VERSION 5.8 ;
BUSBITCHARS "[]" ;
DIVIDERCHAR "/" ;
UNITS
    DATABASE MICRONS 1000 ;
END UNITS

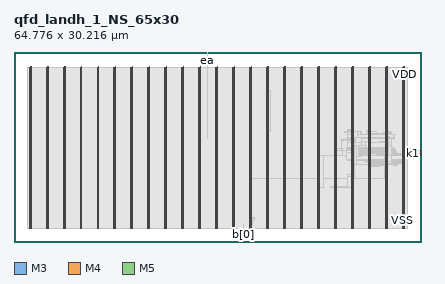
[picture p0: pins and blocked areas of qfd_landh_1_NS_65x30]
MACRO qfd_landh_1_NS_65x30
  FOREIGN qfd_landh_1_NS_65x30 0 0 ;
  CLASS BLOCK ;
  SIZE 64.776 BY 30.216 ;
  PIN a[0]
    DIRECTION INPUT ;
    USE SIGNAL ;
    PORT
      LAYER M3 ;
        RECT  30.708 30.179 30.726 30.216 ;
    END
  END a[0]
  PIN b[0]
    DIRECTION OUTPUT ;
    USE SIGNAL ;
    PORT
      LAYER M3 ;
        RECT  36.468 0 36.486 0.037 ;
    END
  END b[0]
  PIN ck
    DIRECTION INPUT ;
    USE SIGNAL ;
    PORT
      LAYER M4 ;
        RECT  64.692 13.68 64.776 13.704 ;
    END
  END ck
  PIN ckf
    DIRECTION INPUT ;
    USE SIGNAL ;
    PORT
      LAYER M4 ;
        RECT  64.692 13.776 64.776 13.8 ;
    END
  END ckf
  PIN ea
    DIRECTION INPUT ;
    USE SIGNAL ;
    PORT
      LAYER M3 ;
        RECT  30.78 30.179 30.798 30.216 ;
    END
  END ea
  PIN fault
    DIRECTION OUTPUT ;
    USE SIGNAL ;
    PORT
      LAYER M4 ;
        RECT  64.692 13.872 64.776 13.896 ;
    END
  END fault
  PIN k0
    DIRECTION INPUT ;
    USE SIGNAL ;
    PORT
      LAYER M4 ;
        RECT  64.692 13.968 64.776 13.992 ;
    END
  END k0
  PIN k1
    DIRECTION INPUT ;
    USE SIGNAL ;
    PORT
      LAYER M4 ;
        RECT  64.692 14.064 64.776 14.088 ;
    END
  END k1
  PIN k2
    DIRECTION INPUT ;
    USE SIGNAL ;
    PORT
      LAYER M4 ;
        RECT  64.692 14.16 64.776 14.184 ;
    END
  END k2
  PIN rs
    DIRECTION INPUT ;
    USE SIGNAL ;
    PORT
      LAYER M4 ;
        RECT  64.692 14.256 64.776 14.28 ;
    END
  END rs
  PIN tie_hi
    DIRECTION OUTPUT ;
    USE SIGNAL ;
    PORT
      LAYER M4 ;
        RECT  64.692 14.352 64.776 14.376 ;
    END
  END tie_hi
  PIN tie_lo
    DIRECTION OUTPUT ;
    USE SIGNAL ;
    PORT
      LAYER M4 ;
        RECT  64.692 14.448 64.776 14.472 ;
    END
  END tie_lo
  PIN VDD
    DIRECTION INOUT ;
    USE POWER ;
    PORT
      LAYER M5 ;
        RECT  61.992 2.151 62.112 27.833 ;
        RECT  59.292 2.151 59.412 27.833 ;
        RECT  56.592 2.151 56.712 27.833 ;
        RECT  53.892 2.151 54.012 27.833 ;
        RECT  51.192 2.151 51.312 27.833 ;
        RECT  48.492 2.151 48.612 27.833 ;
        RECT  45.792 2.151 45.912 27.833 ;
        RECT  43.092 2.151 43.212 27.833 ;
        RECT  40.392 2.151 40.512 27.833 ;
        RECT  37.692 2.151 37.812 27.833 ;
        RECT  34.992 2.151 35.112 27.833 ;
        RECT  32.292 2.151 32.412 27.833 ;
        RECT  29.592 2.151 29.712 27.833 ;
        RECT  26.892 2.151 27.012 27.833 ;
        RECT  24.192 2.151 24.312 27.833 ;
        RECT  21.492 2.151 21.612 27.833 ;
        RECT  18.792 2.151 18.912 27.833 ;
        RECT  16.092 2.151 16.212 27.833 ;
        RECT  13.392 2.151 13.512 27.833 ;
        RECT  10.692 2.151 10.812 27.833 ;
        RECT  7.992 2.151 8.112 27.833 ;
        RECT  5.292 2.151 5.412 27.833 ;
        RECT  2.592 2.151 2.712 27.833 ;
    END
  END VDD
  PIN VSS
    DIRECTION INOUT ;
    USE GROUND ;
    PORT
      LAYER M5 ;
        RECT  61.8 2.137 61.92 27.819 ;
        RECT  59.1 2.137 59.22 27.819 ;
        RECT  56.4 2.137 56.52 27.819 ;
        RECT  53.7 2.137 53.82 27.819 ;
        RECT  51 2.137 51.12 27.819 ;
        RECT  48.3 2.137 48.42 27.819 ;
        RECT  45.6 2.137 45.72 27.819 ;
        RECT  42.9 2.137 43.02 27.819 ;
        RECT  40.2 2.137 40.32 27.819 ;
        RECT  37.5 2.137 37.62 27.819 ;
        RECT  34.8 2.137 34.92 27.819 ;
        RECT  32.1 2.137 32.22 27.819 ;
        RECT  29.4 2.137 29.52 27.819 ;
        RECT  26.7 2.137 26.82 27.819 ;
        RECT  24 2.137 24.12 27.819 ;
        RECT  21.3 2.137 21.42 27.819 ;
        RECT  18.6 2.137 18.72 27.819 ;
        RECT  15.9 2.137 16.02 27.819 ;
        RECT  13.2 2.137 13.32 27.819 ;
        RECT  10.5 2.137 10.62 27.819 ;
        RECT  7.8 2.137 7.92 27.819 ;
        RECT  5.1 2.137 5.22 27.819 ;
        RECT  2.4 2.137 2.52 27.819 ;
    END
  END VSS
  OBS
    LAYER RVTN ;
     RECT  2.16 2.16 62.586 2.295 ;
     RECT  2.16 2.565 62.586 2.835 ;
     RECT  2.16 3.105 62.586 3.375 ;
     RECT  2.16 3.645 62.586 3.915 ;
     RECT  2.16 4.185 62.586 4.455 ;
     RECT  2.16 4.725 62.586 4.995 ;
     RECT  2.16 5.265 62.586 5.535 ;
     RECT  2.16 5.805 62.586 6.075 ;
     RECT  2.16 6.345 62.586 6.615 ;
     RECT  2.16 6.885 62.586 7.155 ;
     RECT  2.16 7.425 62.586 7.695 ;
     RECT  2.16 7.965 62.586 8.235 ;
     RECT  2.16 8.505 62.586 8.775 ;
     RECT  2.16 9.045 62.586 9.315 ;
     RECT  2.16 9.585 62.586 9.855 ;
     RECT  2.16 10.125 62.586 10.395 ;
     RECT  2.16 10.665 62.586 10.935 ;
     RECT  2.16 11.205 62.586 11.475 ;
     RECT  2.16 11.745 62.586 12.015 ;
     RECT  2.16 12.285 62.586 12.555 ;
     RECT  2.16 12.825 62.586 13.095 ;
     RECT  2.16 13.365 62.586 13.635 ;
     RECT  2.16 13.905 62.586 14.175 ;
     RECT  2.16 14.445 62.586 14.715 ;
     RECT  2.16 14.985 62.586 15.255 ;
     RECT  2.16 15.525 62.586 15.795 ;
     RECT  2.16 16.065 62.586 16.335 ;
     RECT  2.16 16.605 62.586 16.875 ;
     RECT  2.16 17.145 62.586 17.415 ;
     RECT  2.16 17.685 62.586 17.955 ;
     RECT  2.16 18.225 62.586 18.495 ;
     RECT  2.16 18.765 62.586 19.035 ;
     RECT  2.16 19.305 62.586 19.575 ;
     RECT  2.16 19.845 62.586 20.115 ;
     RECT  2.16 20.385 62.586 20.655 ;
     RECT  2.16 20.925 62.586 21.195 ;
     RECT  2.16 21.465 62.586 21.735 ;
     RECT  2.16 22.005 62.586 22.275 ;
     RECT  2.16 22.545 62.586 22.815 ;
     RECT  2.16 23.085 62.586 23.355 ;
     RECT  2.16 23.625 62.586 23.895 ;
     RECT  2.16 24.165 62.586 24.435 ;
     RECT  2.16 24.705 62.586 24.975 ;
     RECT  2.16 25.245 62.586 25.515 ;
     RECT  2.16 25.785 62.586 26.055 ;
     RECT  2.16 26.325 62.586 26.595 ;
     RECT  2.16 26.865 62.586 27.135 ;
     RECT  2.16 27.405 62.586 27.675 ;
    LAYER RVTP ;
     RECT  2.16 2.295 62.586 2.565 ;
     RECT  2.16 2.835 62.586 3.105 ;
     RECT  2.16 3.375 62.586 3.645 ;
     RECT  2.16 3.915 62.586 4.185 ;
     RECT  2.16 4.455 62.586 4.725 ;
     RECT  2.16 4.995 62.586 5.265 ;
     RECT  2.16 5.535 62.586 5.805 ;
     RECT  2.16 6.075 62.586 6.345 ;
     RECT  2.16 6.615 62.586 6.885 ;
     RECT  2.16 7.155 62.586 7.425 ;
     RECT  2.16 7.695 62.586 7.965 ;
     RECT  2.16 8.235 62.586 8.505 ;
     RECT  2.16 8.775 62.586 9.045 ;
     RECT  2.16 9.315 62.586 9.585 ;
     RECT  2.16 9.855 62.586 10.125 ;
     RECT  2.16 10.395 62.586 10.665 ;
     RECT  2.16 10.935 62.586 11.205 ;
     RECT  2.16 11.475 62.586 11.745 ;
     RECT  2.16 12.015 62.586 12.285 ;
     RECT  2.16 12.555 62.586 12.825 ;
     RECT  2.16 13.095 62.586 13.365 ;
     RECT  2.16 13.635 62.586 13.905 ;
     RECT  2.16 14.175 62.586 14.445 ;
     RECT  2.16 14.715 62.586 14.985 ;
     RECT  2.16 15.255 62.586 15.525 ;
     RECT  2.16 15.795 62.586 16.065 ;
     RECT  2.16 16.335 62.586 16.605 ;
     RECT  2.16 16.875 62.586 17.145 ;
     RECT  2.16 17.415 62.586 17.685 ;
     RECT  2.16 17.955 62.586 18.225 ;
     RECT  2.16 18.495 62.586 18.765 ;
     RECT  2.16 19.035 62.586 19.305 ;
     RECT  2.16 19.575 62.586 19.845 ;
     RECT  2.16 20.115 62.586 20.385 ;
     RECT  2.16 20.655 62.586 20.925 ;
     RECT  2.16 21.195 62.586 21.465 ;
     RECT  2.16 21.735 62.586 22.005 ;
     RECT  2.16 22.275 62.586 22.545 ;
     RECT  2.16 22.815 62.586 23.085 ;
     RECT  2.16 23.355 62.586 23.625 ;
     RECT  2.16 23.895 62.586 24.165 ;
     RECT  2.16 24.435 62.586 24.705 ;
     RECT  2.16 24.975 62.586 25.245 ;
     RECT  2.16 25.515 62.586 25.785 ;
     RECT  2.16 26.055 62.586 26.325 ;
     RECT  2.16 26.595 62.586 26.865 ;
     RECT  2.16 27.135 62.586 27.405 ;
     RECT  2.16 27.675 62.586 27.81 ;
    LAYER M1 ;
     RECT  2.16 2.151 62.586 27.819 ;
    LAYER M2 ;
     RECT  2.16 2.151 62.586 27.819 ;
     RECT  62.586 13.536 62.699 15.012 ;
     RECT  62.699 13.536 63.887 14.94 ;
     RECT  63.887 14.922 63.923 14.94 ;
     RECT  63.887 13.842 63.959 14.13 ;
     RECT  63.959 14.112 63.995 14.13 ;
    LAYER M3 ;
     RECT  2.415 2.143 2.505 2.413 ;
     RECT  5.115 2.143 5.205 2.413 ;
     RECT  7.815 2.143 7.905 2.413 ;
     RECT  10.515 2.143 10.605 2.413 ;
     RECT  13.215 2.143 13.305 2.413 ;
     RECT  15.915 2.143 16.005 2.413 ;
     RECT  18.615 2.143 18.705 2.413 ;
     RECT  21.315 2.143 21.405 2.413 ;
     RECT  24.015 2.143 24.105 2.413 ;
     RECT  26.715 2.143 26.805 2.413 ;
     RECT  29.415 2.143 29.505 2.413 ;
     RECT  32.115 2.143 32.205 2.413 ;
     RECT  34.815 2.143 34.905 2.413 ;
     RECT  37.515 2.143 37.605 2.413 ;
     RECT  40.215 2.143 40.305 2.413 ;
     RECT  42.915 2.143 43.005 2.413 ;
     RECT  45.615 2.143 45.705 2.413 ;
     RECT  48.315 2.143 48.405 2.413 ;
     RECT  51.015 2.143 51.105 2.413 ;
     RECT  53.715 2.143 53.805 2.413 ;
     RECT  56.415 2.143 56.505 2.413 ;
     RECT  59.115 2.143 59.205 2.413 ;
     RECT  61.815 2.143 61.905 2.413 ;
     RECT  36.468 0.012 36.486 2.759 ;
     RECT  37.515 2.413 37.797 2.803 ;
     RECT  37.515 2.803 37.854 3.379 ;
     RECT  37.515 3.379 38.214 3.685 ;
     RECT  37.44 3.685 38.214 3.725 ;
     RECT  37.515 3.725 38.214 3.839 ;
     RECT  37.515 3.839 37.998 3.875 ;
     RECT  51.015 2.413 51.297 8.671 ;
     RECT  48.315 2.413 48.597 8.731 ;
     RECT  50.328 8.671 51.297 8.765 ;
     RECT  48.315 8.731 49.014 8.771 ;
     RECT  37.515 3.875 37.797 9.883 ;
     RECT  45.615 2.413 45.897 10.027 ;
     RECT  37.515 9.883 37.89 10.061 ;
     RECT  53.715 2.413 53.997 10.123 ;
     RECT  38.772 10.027 38.79 10.157 ;
     RECT  45.615 10.027 45.99 10.157 ;
     RECT  46.764 10.027 46.782 10.157 ;
     RECT  53.715 10.123 54.126 10.165 ;
     RECT  53.028 10.165 54.126 10.355 ;
     RECT  53.064 10.355 54.126 10.471 ;
     RECT  53.064 10.471 54.198 10.541 ;
     RECT  53.064 10.541 53.997 10.739 ;
     RECT  56.415 2.413 56.697 11.947 ;
     RECT  56.415 11.947 57.402 12.019 ;
     RECT  56.415 12.019 57.474 12.055 ;
     RECT  56.415 12.055 58.122 12.091 ;
     RECT  59.115 2.413 59.397 12.091 ;
     RECT  60.444 12.091 60.966 12.217 ;
     RECT  56.415 12.091 59.454 12.283 ;
     RECT  56.415 12.283 59.598 12.361 ;
     RECT  60.336 12.217 60.966 12.361 ;
     RECT  56.415 12.361 60.966 12.523 ;
     RECT  56.415 12.523 61.002 12.595 ;
     RECT  61.815 2.413 62.097 12.595 ;
     RECT  56.415 12.595 62.097 12.721 ;
     RECT  56.268 12.721 62.097 12.757 ;
     RECT  56.088 12.757 62.097 12.829 ;
     RECT  53.715 10.739 53.997 12.865 ;
     RECT  53.64 12.865 54.414 12.901 ;
     RECT  55.692 12.829 62.097 12.901 ;
     RECT  53.064 12.901 54.594 13.027 ;
     RECT  55.368 12.901 62.097 13.027 ;
     RECT  53.064 13.027 62.097 13.051 ;
     RECT  52.884 13.051 62.097 13.091 ;
     RECT  53.496 13.091 62.097 13.771 ;
     RECT  63.864 13.531 63.882 13.837 ;
     RECT  53.496 13.771 62.73 13.909 ;
     RECT  63.864 13.837 63.954 14.107 ;
     RECT  53.244 13.909 62.73 14.135 ;
     RECT  53.244 14.135 60.822 14.203 ;
     RECT  63.864 14.107 63.99 14.285 ;
     RECT  52.776 14.203 60.822 14.369 ;
     RECT  61.815 14.135 62.73 14.443 ;
     RECT  63.864 14.285 63.918 14.443 ;
     RECT  52.776 14.369 60.714 14.525 ;
     RECT  52.92 14.525 60.714 14.549 ;
     RECT  52.92 14.549 60.642 14.639 ;
     RECT  61.815 14.443 63.918 14.639 ;
     RECT  52.92 14.639 60.57 14.909 ;
     RECT  63.9 14.639 63.918 14.945 ;
     RECT  52.92 14.909 60.426 15.017 ;
     RECT  61.815 14.639 62.694 15.017 ;
     RECT  53.028 15.017 60.426 15.053 ;
     RECT  53.028 15.053 60.03 15.755 ;
     RECT  52.092 14.827 52.11 16.033 ;
     RECT  52.092 16.033 52.254 16.105 ;
     RECT  53.028 15.755 54.27 16.105 ;
     RECT  52.092 16.105 54.27 16.259 ;
     RECT  52.092 16.259 52.11 16.403 ;
     RECT  52.884 16.259 54.27 16.403 ;
     RECT  55.188 15.755 60.03 16.501 ;
     RECT  52.992 16.403 54.27 16.555 ;
     RECT  55.188 16.501 60.462 16.555 ;
     RECT  52.992 16.555 60.462 17.069 ;
     RECT  52.992 17.069 60.246 17.105 ;
     RECT  56.124 17.105 59.958 17.249 ;
     RECT  58.68 17.249 59.958 17.339 ;
     RECT  58.68 17.339 59.814 17.411 ;
     RECT  52.992 17.105 55.314 17.491 ;
     RECT  52.596 17.491 55.314 17.609 ;
     RECT  56.124 17.249 57.69 17.609 ;
     RECT  59.115 17.411 59.814 17.609 ;
     RECT  40.215 2.413 40.497 17.617 ;
     RECT  52.992 17.609 54.054 17.645 ;
     RECT  55.044 17.609 55.062 17.645 ;
     RECT  57.672 17.609 57.69 17.645 ;
     RECT  52.992 17.645 53.997 17.681 ;
     RECT  56.124 17.609 56.697 17.681 ;
     RECT  53.064 17.681 53.997 17.879 ;
     RECT  40.215 17.617 40.77 24.089 ;
     RECT  30.708 16.537 30.726 24.097 ;
     RECT  2.415 2.413 2.697 27.557 ;
     RECT  5.115 2.413 5.397 27.557 ;
     RECT  7.815 2.413 8.097 27.557 ;
     RECT  10.515 2.413 10.797 27.557 ;
     RECT  13.215 2.413 13.497 27.557 ;
     RECT  15.915 2.413 16.197 27.557 ;
     RECT  18.615 2.413 18.897 27.557 ;
     RECT  21.315 2.413 21.597 27.557 ;
     RECT  24.015 2.413 24.297 27.557 ;
     RECT  26.715 2.413 26.997 27.557 ;
     RECT  29.415 2.413 29.697 27.557 ;
     RECT  32.115 2.413 32.397 27.557 ;
     RECT  34.815 2.413 35.097 27.557 ;
     RECT  37.515 10.061 37.797 27.557 ;
     RECT  40.215 24.089 40.497 27.557 ;
     RECT  42.915 2.413 43.197 27.557 ;
     RECT  45.615 10.157 45.897 27.557 ;
     RECT  48.315 8.771 48.597 27.557 ;
     RECT  51.015 8.765 51.297 27.557 ;
     RECT  53.715 17.879 53.997 27.557 ;
     RECT  56.415 17.681 56.697 27.557 ;
     RECT  59.115 17.609 59.397 27.557 ;
     RECT  61.815 15.017 62.097 27.557 ;
     RECT  2.607 27.557 2.697 27.827 ;
     RECT  5.307 27.557 5.397 27.827 ;
     RECT  8.007 27.557 8.097 27.827 ;
     RECT  10.707 27.557 10.797 27.827 ;
     RECT  13.407 27.557 13.497 27.827 ;
     RECT  16.107 27.557 16.197 27.827 ;
     RECT  18.807 27.557 18.897 27.827 ;
     RECT  21.507 27.557 21.597 27.827 ;
     RECT  24.207 27.557 24.297 27.827 ;
     RECT  26.907 27.557 26.997 27.827 ;
     RECT  29.607 27.557 29.697 27.827 ;
     RECT  32.307 27.557 32.397 27.827 ;
     RECT  35.007 27.557 35.097 27.827 ;
     RECT  37.707 27.557 37.797 27.827 ;
     RECT  40.407 27.557 40.497 27.827 ;
     RECT  43.107 27.557 43.197 27.827 ;
     RECT  45.807 27.557 45.897 27.827 ;
     RECT  48.507 27.557 48.597 27.827 ;
     RECT  51.207 27.557 51.297 27.827 ;
     RECT  53.907 27.557 53.997 27.827 ;
     RECT  56.607 27.557 56.697 27.827 ;
     RECT  59.307 27.557 59.397 27.827 ;
     RECT  62.007 27.557 62.097 27.827 ;
     RECT  30.708 24.097 30.798 30.204 ;
    LAYER M4 ;
     RECT  2.408 2.148 2.512 27.552 ;
     RECT  2.512 2.418 2.6 27.552 ;
     RECT  2.6 2.418 2.704 27.822 ;
     RECT  5.108 2.148 5.212 27.552 ;
     RECT  5.212 2.418 5.3 27.552 ;
     RECT  5.3 2.418 5.404 27.822 ;
     RECT  7.808 2.148 7.912 27.552 ;
     RECT  7.912 2.418 8 27.552 ;
     RECT  8 2.418 8.104 27.822 ;
     RECT  10.508 2.148 10.612 27.552 ;
     RECT  10.612 2.418 10.7 27.552 ;
     RECT  10.7 2.418 10.804 27.822 ;
     RECT  13.208 2.148 13.312 27.552 ;
     RECT  13.312 2.418 13.4 27.552 ;
     RECT  13.4 2.418 13.504 27.822 ;
     RECT  15.908 2.148 16.012 27.552 ;
     RECT  16.012 2.418 16.1 27.552 ;
     RECT  16.1 2.418 16.204 27.822 ;
     RECT  18.608 2.148 18.712 27.552 ;
     RECT  18.712 2.418 18.8 27.552 ;
     RECT  18.8 2.418 18.904 27.822 ;
     RECT  21.308 2.148 21.412 27.552 ;
     RECT  21.412 2.418 21.5 27.552 ;
     RECT  21.5 2.418 21.604 27.822 ;
     RECT  24.008 2.148 24.112 27.552 ;
     RECT  24.112 2.418 24.2 27.552 ;
     RECT  24.2 2.418 24.304 27.822 ;
     RECT  26.708 2.148 26.812 27.552 ;
     RECT  26.812 2.418 26.9 27.552 ;
     RECT  26.9 2.418 27.004 27.822 ;
     RECT  29.408 2.148 29.512 27.552 ;
     RECT  29.512 2.418 29.6 27.552 ;
     RECT  29.6 2.418 29.704 27.822 ;
     RECT  32.108 2.148 32.212 27.552 ;
     RECT  32.212 2.418 32.3 27.552 ;
     RECT  32.3 2.418 32.404 27.822 ;
     RECT  34.808 2.148 34.912 27.552 ;
     RECT  34.912 2.418 35 27.552 ;
     RECT  35 2.418 35.104 27.822 ;
     RECT  37.381 3.696 37.508 3.72 ;
     RECT  37.381 9.888 37.508 9.912 ;
     RECT  37.508 2.148 37.612 27.552 ;
     RECT  37.612 2.418 37.7 27.552 ;
     RECT  37.7 2.418 37.804 27.822 ;
     RECT  37.804 9.888 37.901 10.152 ;
     RECT  37.901 10.032 38.801 10.152 ;
     RECT  38.801 10.128 40.208 10.152 ;
     RECT  40.208 2.148 40.312 27.552 ;
     RECT  40.312 2.418 40.4 27.552 ;
     RECT  40.4 2.418 40.504 27.822 ;
     RECT  40.504 10.128 42.908 10.152 ;
     RECT  42.908 2.148 43.012 27.552 ;
     RECT  43.012 2.418 43.1 27.552 ;
     RECT  43.1 2.418 43.204 27.822 ;
     RECT  43.204 10.128 45.608 10.152 ;
     RECT  45.608 2.148 45.712 27.552 ;
     RECT  45.712 2.418 45.8 27.552 ;
     RECT  45.8 2.418 45.904 27.822 ;
     RECT  45.904 10.032 46.793 10.152 ;
     RECT  46.793 10.128 48.308 10.152 ;
     RECT  48.308 2.148 48.412 27.552 ;
     RECT  48.412 2.418 48.5 27.552 ;
     RECT  48.5 2.418 48.604 27.822 ;
     RECT  48.604 8.736 49.283 8.76 ;
     RECT  50.317 8.736 51.008 8.76 ;
     RECT  48.604 10.128 51.008 10.152 ;
     RECT  48.604 13.68 51.008 13.704 ;
     RECT  51.008 2.148 51.112 27.552 ;
     RECT  51.112 2.418 51.2 27.552 ;
     RECT  51.2 2.418 51.304 27.822 ;
     RECT  51.304 13.68 52.165 14.856 ;
     RECT  52.165 13.68 52.844 14.52 ;
     RECT  51.304 10.128 53.017 10.152 ;
     RECT  53.017 10.128 53.053 10.344 ;
     RECT  51.304 8.736 53.708 8.76 ;
     RECT  53.053 10.128 53.708 10.728 ;
     RECT  52.844 13.056 53.708 14.52 ;
     RECT  53.708 2.148 53.812 27.552 ;
     RECT  53.812 2.418 53.9 27.552 ;
     RECT  53.9 2.418 54.004 27.822 ;
     RECT  54.004 10.128 54.227 10.728 ;
     RECT  54.004 12.288 54.425 15.384 ;
     RECT  54.004 16.56 54.677 17.496 ;
     RECT  54.425 13.584 54.821 15.384 ;
     RECT  54.821 14.928 54.857 15.384 ;
     RECT  54.677 17.04 55.181 17.496 ;
     RECT  54.857 15.36 55.285 15.384 ;
     RECT  54.821 13.584 55.325 13.704 ;
     RECT  55.181 17.472 55.325 17.496 ;
     RECT  55.285 15.36 55.969 16.008 ;
     RECT  55.325 13.68 56.293 13.704 ;
     RECT  54.227 10.128 56.408 10.152 ;
     RECT  54.425 12.288 56.408 12.312 ;
     RECT  56.293 13.68 56.408 13.896 ;
     RECT  55.969 14.976 56.408 16.008 ;
     RECT  56.408 2.148 56.512 27.552 ;
     RECT  56.512 2.418 56.6 27.552 ;
     RECT  56.6 2.418 56.704 27.822 ;
     RECT  56.704 17.04 57.593 17.112 ;
     RECT  56.704 13.68 57.665 14.04 ;
     RECT  57.593 17.04 57.665 17.064 ;
     RECT  57.665 13.68 58.705 13.896 ;
     RECT  56.704 12.288 58.837 12.312 ;
     RECT  58.837 12.288 58.849 12.552 ;
     RECT  58.705 13.68 58.849 14.76 ;
     RECT  58.849 12.288 59.101 14.76 ;
     RECT  58.093 15.984 59.101 16.008 ;
     RECT  56.704 10.128 59.108 10.152 ;
     RECT  59.101 12.288 59.108 16.008 ;
     RECT  59.108 2.148 59.212 27.552 ;
     RECT  59.212 2.418 59.3 27.552 ;
     RECT  59.3 2.418 59.404 27.822 ;
     RECT  59.404 13.68 59.603 16.824 ;
     RECT  59.404 12.288 59.609 12.552 ;
     RECT  59.603 16.8 59.644 16.824 ;
     RECT  59.603 13.68 60.041 15.288 ;
     RECT  60.041 13.68 60.077 15 ;
     RECT  60.077 13.68 60.113 14.856 ;
     RECT  59.609 12.528 61.808 12.552 ;
     RECT  60.113 13.68 61.808 13.896 ;
     RECT  61.808 2.148 61.912 27.552 ;
     RECT  61.912 2.418 62 27.552 ;
     RECT  62 2.418 62.104 27.822 ;
     RECT  62.104 13.68 63.277 14.376 ;
     RECT  63.277 13.68 64.716 14.472 ;
    LAYER M5 ;
     RECT  2.4 2.137 2.52 2.151 ;
     RECT  5.1 2.137 5.22 2.151 ;
     RECT  7.8 2.137 7.92 2.151 ;
     RECT  10.5 2.137 10.62 2.151 ;
     RECT  13.2 2.137 13.32 2.151 ;
     RECT  15.9 2.137 16.02 2.151 ;
     RECT  18.6 2.137 18.72 2.151 ;
     RECT  21.3 2.137 21.42 2.151 ;
     RECT  24 2.137 24.12 2.151 ;
     RECT  26.7 2.137 26.82 2.151 ;
     RECT  29.4 2.137 29.52 2.151 ;
     RECT  32.1 2.137 32.22 2.151 ;
     RECT  34.8 2.137 34.92 2.151 ;
     RECT  37.5 2.137 37.62 2.151 ;
     RECT  40.2 2.137 40.32 2.151 ;
     RECT  42.9 2.137 43.02 2.151 ;
     RECT  45.6 2.137 45.72 2.151 ;
     RECT  48.3 2.137 48.42 2.151 ;
     RECT  51 2.137 51.12 2.151 ;
     RECT  53.7 2.137 53.82 2.151 ;
     RECT  56.4 2.137 56.52 2.151 ;
     RECT  59.1 2.137 59.22 2.151 ;
     RECT  61.8 2.137 61.92 2.151 ;
     RECT  37.5 2.151 37.812 3.685 ;
     RECT  48.3 2.151 48.612 8.725 ;
     RECT  53.7 2.151 54.012 8.725 ;
     RECT  37.392 3.685 37.812 9.923 ;
     RECT  59.1 2.151 59.412 10.117 ;
     RECT  53.04 8.725 54.012 10.355 ;
     RECT  53.7 10.355 54.012 10.501 ;
     RECT  58.944 10.117 59.412 12.277 ;
     RECT  53.7 10.501 54.216 12.323 ;
     RECT  58.848 12.277 59.412 12.517 ;
     RECT  58.848 12.517 60.072 12.563 ;
     RECT  58.944 12.563 60.072 12.755 ;
     RECT  53.7 12.323 54.168 13.045 ;
     RECT  48.3 8.725 49.272 13.715 ;
     RECT  59.1 12.755 60.072 13.811 ;
     RECT  56.4 2.151 56.712 13.861 ;
     RECT  52.896 13.045 54.168 14.243 ;
     RECT  51 2.151 51.312 14.485 ;
     RECT  51 14.485 52.152 14.867 ;
     RECT  56.304 13.861 56.712 15.011 ;
     RECT  59.1 13.811 59.412 15.301 ;
     RECT  53.7 14.243 54.168 16.595 ;
     RECT  59.1 15.301 59.592 16.835 ;
     RECT  2.4 2.151 2.712 27.819 ;
     RECT  5.1 2.151 5.412 27.819 ;
     RECT  7.8 2.151 8.112 27.819 ;
     RECT  10.5 2.151 10.812 27.819 ;
     RECT  13.2 2.151 13.512 27.819 ;
     RECT  15.9 2.151 16.212 27.819 ;
     RECT  18.6 2.151 18.912 27.819 ;
     RECT  21.3 2.151 21.612 27.819 ;
     RECT  24 2.151 24.312 27.819 ;
     RECT  26.7 2.151 27.012 27.819 ;
     RECT  29.4 2.151 29.712 27.819 ;
     RECT  32.1 2.151 32.412 27.819 ;
     RECT  34.8 2.151 35.112 27.819 ;
     RECT  37.5 9.923 37.812 27.819 ;
     RECT  40.2 2.151 40.512 27.819 ;
     RECT  42.9 2.151 43.212 27.819 ;
     RECT  45.6 2.151 45.912 27.819 ;
     RECT  48.3 13.715 48.612 27.819 ;
     RECT  51 14.867 51.312 27.819 ;
     RECT  53.7 16.595 54.012 27.819 ;
     RECT  56.4 15.011 56.712 27.819 ;
     RECT  59.1 16.835 59.412 27.819 ;
     RECT  61.8 2.151 62.112 27.819 ;
     RECT  2.592 27.819 2.712 27.833 ;
     RECT  5.292 27.819 5.412 27.833 ;
     RECT  7.992 27.819 8.112 27.833 ;
     RECT  10.692 27.819 10.812 27.833 ;
     RECT  13.392 27.819 13.512 27.833 ;
     RECT  16.092 27.819 16.212 27.833 ;
     RECT  18.792 27.819 18.912 27.833 ;
     RECT  21.492 27.819 21.612 27.833 ;
     RECT  24.192 27.819 24.312 27.833 ;
     RECT  26.892 27.819 27.012 27.833 ;
     RECT  29.592 27.819 29.712 27.833 ;
     RECT  32.292 27.819 32.412 27.833 ;
     RECT  34.992 27.819 35.112 27.833 ;
     RECT  37.692 27.819 37.812 27.833 ;
     RECT  40.392 27.819 40.512 27.833 ;
     RECT  43.092 27.819 43.212 27.833 ;
     RECT  45.792 27.819 45.912 27.833 ;
     RECT  48.492 27.819 48.612 27.833 ;
     RECT  51.192 27.819 51.312 27.833 ;
     RECT  53.892 27.819 54.012 27.833 ;
     RECT  56.592 27.819 56.712 27.833 ;
     RECT  59.292 27.819 59.412 27.833 ;
     RECT  61.992 27.819 62.112 27.833 ;
  END
END qfd_landh_1_NS_65x30
END LIBRARY
